VERSION 5.7 ;
BUSBITCHARS "[]" ;
DIVIDERCHAR "/" ;

PROPERTYDEFINITIONS
  LAYER LEF58_TYPE STRING ;
END PROPERTYDEFINITIONS

UNITS
  DATABASE MICRONS 1000 ;
END UNITS
MANUFACTURINGGRID 0.05 ;
LAYER OVERLAP
  TYPE OVERLAP ;
END OVERLAP

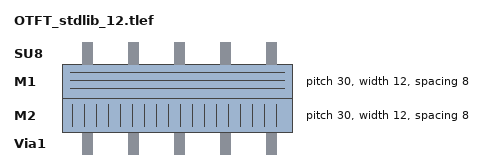
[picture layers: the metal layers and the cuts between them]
LAYER Via1
  TYPE CUT ;
END Via1

LAYER M2
  TYPE ROUTING ;
  DIRECTION VERTICAL ;
  PITCH 30 30 ;
  WIDTH 12 ;
  OFFSET 15 15 ;
  SPACING 8 ;
END M2

LAYER M1
  TYPE ROUTING ;
  DIRECTION HORIZONTAL ;
  PITCH 30 30 ;
  WIDTH 12 ;
  OFFSET 15 15 ;
  SPACING 8 ;
END M1

LAYER SU8
  TYPE CUT ;
  PROPERTY LEF58_TYPE "TYPE PASSIVATION ;" ;
END SU8

VIARULE M2_M1 GENERATE DEFAULT
  LAYER M1 ;
    ENCLOSURE 6 6 ;
  LAYER M2 ;
    ENCLOSURE 6 6 ;
  LAYER Via1 ;
    RECT -4 -4 4 4 ;
    SPACING 13 BY 13 ;
    RESISTANCE 5.000000 ;
END M2_M1

NONDEFAULTRULE virtuosoDefaultExtractorSetup
  LAYER M1
    WIDTH 12 ;
  END M1
  LAYER M2
    WIDTH 12 ;
  END M2
  USEVIARULE M2_M1 ;
  USEVIARULE M2_MC ;
END virtuosoDefaultExtractorSetup
SITE CoreSite
  CLASS CORE ;
  SYMMETRY Y ;
  SIZE 10 BY 900 ;
END CoreSite

END LIBRARY
